VERSION 5.8 ;
BUSBITCHARS "[]" ;
DIVIDERCHAR "/" ;
UNITS
 DATABASE MICRONS 2000 ;
END UNITS
LAYER M1
 TYPE ROUTING ;
 DIRECTION HORIZONTAL ;
 PITCH 0.2 ;
 WIDTH 0.1 ;
 SPACING 0.1 ;
END M1
SITE CoreSite
 CLASS CORE ;
 SYMMETRY X Y ;
 SIZE 1 BY 4 ;
END CoreSite
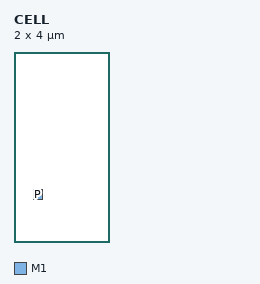
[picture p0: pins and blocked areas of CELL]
MACRO CELL
 CLASS CORE ;
 ORIGIN 0 0 ;
 SIZE 2 BY 4 ;
 SYMMETRY X Y R90 ;
 SITE CoreSite ;
 PIN P
  DIRECTION INOUT ;
  PORT
   LAYER M1 ;
   RECT 0.4 0.9 0.6 1.1 ;
  END
 END P
END CELL
END LIBRARY
